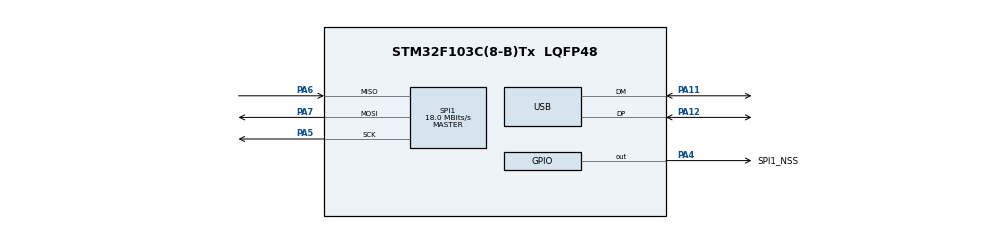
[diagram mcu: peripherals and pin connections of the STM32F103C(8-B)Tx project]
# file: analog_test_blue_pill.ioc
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Mcu.Family=STM32F1
Mcu.Name=STM32F103C(8-B)Tx
Mcu.Package=LQFP48
NVIC.PriorityGroup=NVIC_PRIORITYGROUP_4
NVIC.TIM3_IRQn=true\:0\:0\:false\:false\:true\:true
NVIC.USB_LP_CAN1_RX0_IRQn=true\:0\:0\:false\:false\:true\:true
PA11.Mode=Device
PA11.Signal=USB_DM
PA12.Mode=Device
PA12.Signal=USB_DP
PA13.Mode=Serial_Wire
PA13.Signal=SYS_JTMS-SWDIO
PA14.Mode=Serial_Wire
PA14.Signal=SYS_JTCK-SWCLK
PA4.GPIO_Label=SPI1_NSS
PA4.GPIO_Speed=GPIO_SPEED_FREQ_HIGH
PA4.Signal=GPIO_Output
PA5.Mode=Full_Duplex_Master
PA5.Signal=SPI1_SCK
PA6.Mode=Full_Duplex_Master
PA6.Signal=SPI1_MISO
PA7.Mode=Full_Duplex_Master
PA7.Signal=SPI1_MOSI
PC14-OSC32_IN.Mode=LSE-External-Oscillator
PC14-OSC32_IN.Signal=RCC_OSC32_IN
PC15-OSC32_OUT.Mode=LSE-External-Oscillator
PC15-OSC32_OUT.Signal=RCC_OSC32_OUT
PD0-OSC_IN.Mode=HSE-External-Oscillator
PD0-OSC_IN.Signal=RCC_OSC_IN
PD1-OSC_OUT.Mode=HSE-External-Oscillator
PD1-OSC_OUT.Signal=RCC_OSC_OUT
ProjectManager.HeapSize=0x200
ProjectManager.StackSize=0x400
ProjectManager.TargetToolchain=SW4STM32
RCC.ADCPresc=RCC_ADCPCLK2_DIV4
RCC.AHBFreq_Value=72000000
RCC.APB1CLKDivider=RCC_HCLK_DIV2
RCC.APB1Freq_Value=36000000
RCC.APB1TimFreq_Value=72000000
RCC.APB2Freq_Value=72000000
RCC.APB2TimFreq_Value=72000000
RCC.HCLKFreq_Value=72000000
RCC.PLLMUL=RCC_PLL_MUL9
RCC.SYSCLKFreq_VALUE=72000000
RCC.SYSCLKSource=RCC_SYSCLKSOURCE_PLLCLK
RCC.USBFreq_Value=48000000
RCC.USBPrescaler=RCC_USBCLKSOURCE_PLL_DIV1_5
RCC.VDD_VALUE=3.3
SPI1.BaudRatePrescaler=SPI_BAUDRATEPRESCALER_4
SPI1.CalculateBaudRate=18.0 MBits/s
SPI1.DataSize=SPI_DATASIZE_16BIT
SPI1.Direction=SPI_DIRECTION_2LINES
SPI1.Mode=SPI_MODE_MASTER
SPI1.VirtualType=VM_MASTER
TIM3.Period=9
TIM3.Prescaler=719
USB.ep0_mps=DEP0CTL_MPS_64
USB_DEVICE.CLASS_NAME_FS=CDC
USB_DEVICE.MANUFACTURER_STRING=Yandex, LLC.
USB_DEVICE.PRODUCT_STRING_CDC_FS=VoltaBox
USB_DEVICE.USBD_CDC_INTERVAL=10
USB_DEVICE.USBD_HandleTypeDef=hUsbDeviceFS
USB_DEVICE.USBD_SELF_POWERED=0
USB_DEVICE.USBD_SUPPORT_USER_STRING=0
USB_DEVICE.VirtualMode=Cdc
USB_DEVICE.VirtualModeFS=Cdc_FS
VP_TIM3_VS_ClockSourceINT.Mode=Internal
VP_USB_DEVICE_VS_USB_DEVICE_CDC_FS.Mode=CDC_FS
board=custom

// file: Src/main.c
/**
  ******************************************************************************
  * @file           : main.c
  * @brief          : Main program body
  ******************************************************************************
  * This notice applies to any and all portions of this file
  * that are not between comment pairs USER CODE BEGIN and
  * USER CODE END. Other portions of this file, whether
  * inserted by the user or by software development tools
  * are owned by their respective copyright owners.
  *
  * Copyright (c) 2018 STMicroelectronics International N.V.
  * All rights reserved.
  *
  * Redistribution and use in source and binary forms, with or without
  * modification, are permitted, provided that the following conditions are met:
  *
  * 1. Redistribution of source code must retain the above copyright notice,
  *    this list of conditions and the following disclaimer.
  * 2. Redistributions in binary form must reproduce the above copyright notice,
  *    this list of conditions and the following disclaimer in the documentation
  *    and/or other materials provided with the distribution.
  * 3. Neither the name of STMicroelectronics nor the names of other
  *    contributors to this software may be used to endorse or promote products
  *    derived from this software without specific written permission.
  * 4. This software, including modifications and/or derivative works of this
  *    software, must execute solely and exclusively on microcontroller or
  *    microprocessor devices manufactured by or for STMicroelectronics.
  * 5. Redistribution and use of this software other than as permitted under
  *    this license is void and will automatically terminate your rights under
  *    this license.
  *
  * THIS SOFTWARE IS PROVIDED BY STMICROELECTRONICS AND CONTRIBUTORS "AS IS"
  * AND ANY EXPRESS, IMPLIED OR STATUTORY WARRANTIES, INCLUDING, BUT NOT
  * LIMITED TO, THE IMPLIED WARRANTIES OF MERCHANTABILITY, FITNESS FOR A
  * PARTICULAR PURPOSE AND NON-INFRINGEMENT OF THIRD PARTY INTELLECTUAL PROPERTY
  * RIGHTS ARE DISCLAIMED TO THE FULLEST EXTENT PERMITTED BY LAW. IN NO EVENT
  * SHALL STMICROELECTRONICS OR CONTRIBUTORS BE LIABLE FOR ANY DIRECT, INDIRECT,
  * INCIDENTAL, SPECIAL, EXEMPLARY, OR CONSEQUENTIAL DAMAGES (INCLUDING, BUT NOT
  * LIMITED TO, PROCUREMENT OF SUBSTITUTE GOODS OR SERVICES; LOSS OF USE, DATA,
  * OR PROFITS; OR BUSINESS INTERRUPTION) HOWEVER CAUSED AND ON ANY THEORY OF
  * LIABILITY, WHETHER IN CONTRACT, STRICT LIABILITY, OR TORT (INCLUDING
  * NEGLIGENCE OR OTHERWISE) ARISING IN ANY WAY OUT OF THE USE OF THIS SOFTWARE,
  * EVEN IF ADVISED OF THE POSSIBILITY OF SUCH DAMAGE.
  *
  ******************************************************************************
  */
#include "main.h"
#include "stm32f1xx_hal.h"
#include "usb_device.h"

/* USER CODE BEGIN Includes */
#include "usbd_cdc_if.h"
#include "buffer.h"

#define SENDBUF_SIZE RINGBUF_SIZE/2
/* USER CODE END Includes */

SPI_HandleTypeDef hspi1;

TIM_HandleTypeDef htim3;

/* USER CODE BEGIN PV */
/* Private variables ---------------------------------------------------------*/
const uint8_t cmd_read_current[] = { 0x03, 0x82, 0x00, 0x00 };
const uint8_t cmd_read_voltage[] = { 0x01, 0x82, 0x00, 0x00 };
struct ringbuf_t rb;

/* USER CODE END PV */

void SystemClock_Config(void);
static void MX_GPIO_Init(void);
static void MX_SPI1_Init(void);
static void MX_TIM3_Init(void);

/* USER CODE BEGIN PFP */
/* Private function prototypes -----------------------------------------------*/

/* USER CODE END PFP */

/* USER CODE BEGIN 0 */
uint8_t overSampleCount = 0;
uint16_t overSampleISum = 0;
uint16_t overSampleUSum = 0;
void HAL_TIM_PeriodElapsedCallback(TIM_HandleTypeDef *htim) {
  if (htim->Instance == TIM3) {
    HAL_StatusTypeDef status;
    uint8_t receive_buffer[] = { 0x00, 0x00, 0x00, 0x00 };

    HAL_GPIO_WritePin(SPI1_NSS_GPIO_Port, SPI1_NSS_Pin, GPIO_PIN_RESET);
    status = HAL_SPI_TransmitReceive(&hspi1, cmd_read_current, receive_buffer,
        2, HAL_MAX_DELAY);
    HAL_GPIO_WritePin(SPI1_NSS_GPIO_Port, SPI1_NSS_Pin, GPIO_PIN_SET);
    uint16_t current_value = ((uint16_t) receive_buffer[3] << 8)
        + (uint16_t) receive_buffer[2];
    HAL_GPIO_WritePin(SPI1_NSS_GPIO_Port, SPI1_NSS_Pin, GPIO_PIN_RESET);
    status = HAL_SPI_TransmitReceive(&hspi1, cmd_read_voltage, receive_buffer,
        2, HAL_MAX_DELAY);
    HAL_GPIO_WritePin(SPI1_NSS_GPIO_Port, SPI1_NSS_Pin, GPIO_PIN_SET);
    uint16_t voltage_value = ((uint16_t) receive_buffer[3] << 8)
        + (uint16_t) receive_buffer[2];

    //rb_push(&rb, current_value);
    if(status == HAL_OK)
    {
      if(overSampleCount < 4)
      {
        overSampleISum += current_value;
        overSampleUSum += voltage_value;
        overSampleCount++;
      }
      else
      {
        overSampleCount = 0;
        rb_push(&rb, overSampleISum);
        //rb_push(&rb, overSampleUSum);
        overSampleISum = 0;
        overSampleUSum = 0;
      }
    }
  }
}
/* USER CODE END 0 */

int main(void)
{
  /* USER CODE BEGIN 1 */
  uint16_t buff[16];
  rb_init(&rb);

  /* USER CODE END 1 */

  /* MCU Configuration----------------------------------------------------------*/

  /* Reset of all peripherals, Initializes the Flash interface and the Systick. */
  HAL_Init();

  /* Configure the system clock */
  SystemClock_Config();

  /* Initialize all configured peripherals */
  MX_GPIO_Init();
  MX_USB_DEVICE_Init();
  MX_SPI1_Init();
  MX_TIM3_Init();
  /* USER CODE BEGIN 2 */

  // wait USB enumeration
  HAL_Delay(1000);

  HAL_TIM_Base_Start_IT(&htim3);

  /* USER CODE END 2 */

  /* Infinite loop */
  while (1) {

  /* USER CODE BEGIN 3 */
    if (rb_remain(&rb) > SENDBUF_SIZE) {
      for (int i = 0; i < SENDBUF_SIZE; i++)
        buff[i] = rb_pop(&rb);
      while (CDC_Transmit_FS((uint8_t*) buff, sizeof(buff)) == USBD_BUSY)
        ;
    }

  }
  /* USER CODE END 3 */

}

void SystemClock_Config(void)
{

  RCC_OscInitTypeDef RCC_OscInitStruct;
  RCC_ClkInitTypeDef RCC_ClkInitStruct;
  RCC_PeriphCLKInitTypeDef PeriphClkInit;

    /**Initializes the CPU, AHB and APB busses clocks
    */
  RCC_OscInitStruct.OscillatorType = RCC_OSCILLATORTYPE_HSE;
  RCC_OscInitStruct.HSEState = RCC_HSE_ON;
  RCC_OscInitStruct.HSEPredivValue = RCC_HSE_PREDIV_DIV1;
  RCC_OscInitStruct.HSIState = RCC_HSI_ON;
  RCC_OscInitStruct.PLL.PLLState = RCC_PLL_ON;
  RCC_OscInitStruct.PLL.PLLSource = RCC_PLLSOURCE_HSE;
  RCC_OscInitStruct.PLL.PLLMUL = RCC_PLL_MUL6;
  if (HAL_RCC_OscConfig(&RCC_OscInitStruct) != HAL_OK)
  {
    _Error_Handler(__FILE__, __LINE__);
  }

    /**Initializes the CPU, AHB and APB busses clocks
    */
  RCC_ClkInitStruct.ClockType = RCC_CLOCKTYPE_HCLK|RCC_CLOCKTYPE_SYSCLK
                              |RCC_CLOCKTYPE_PCLK1|RCC_CLOCKTYPE_PCLK2;
  RCC_ClkInitStruct.SYSCLKSource = RCC_SYSCLKSOURCE_PLLCLK;
  RCC_ClkInitStruct.AHBCLKDivider = RCC_SYSCLK_DIV1;
  RCC_ClkInitStruct.APB1CLKDivider = RCC_HCLK_DIV2;
  RCC_ClkInitStruct.APB2CLKDivider = RCC_HCLK_DIV1;

  if (HAL_RCC_ClockConfig(&RCC_ClkInitStruct, FLASH_LATENCY_1) != HAL_OK)
  {
    _Error_Handler(__FILE__, __LINE__);
  }

  PeriphClkInit.PeriphClockSelection = RCC_PERIPHCLK_USB;
  PeriphClkInit.UsbClockSelection = RCC_USBCLKSOURCE_PLL;
  if (HAL_RCCEx_PeriphCLKConfig(&PeriphClkInit) != HAL_OK)
  {
    _Error_Handler(__FILE__, __LINE__);
  }

    /**Configure the Systick interrupt time
    */
  HAL_SYSTICK_Config(HAL_RCC_GetHCLKFreq()/1000);

    /**Configure the Systick
    */
  HAL_SYSTICK_CLKSourceConfig(SYSTICK_CLKSOURCE_HCLK);

  /* SysTick_IRQn interrupt configuration */
  HAL_NVIC_SetPriority(SysTick_IRQn, 0, 0);
}

/* SPI1 init function */
static void MX_SPI1_Init(void)
{

  /* SPI1 parameter configuration*/
  hspi1.Instance = SPI1;
  hspi1.Init.Mode = SPI_MODE_MASTER;
  hspi1.Init.Direction = SPI_DIRECTION_2LINES;
  hspi1.Init.DataSize = SPI_DATASIZE_16BIT;
  hspi1.Init.CLKPolarity = SPI_POLARITY_LOW;
  hspi1.Init.CLKPhase = SPI_PHASE_1EDGE;
  hspi1.Init.NSS = SPI_NSS_SOFT;
  hspi1.Init.BaudRatePrescaler = SPI_BAUDRATEPRESCALER_4;
  hspi1.Init.FirstBit = SPI_FIRSTBIT_MSB;
  hspi1.Init.TIMode = SPI_TIMODE_DISABLE;
  hspi1.Init.CRCCalculation = SPI_CRCCALCULATION_DISABLE;
  hspi1.Init.CRCPolynomial = 10;
  if (HAL_SPI_Init(&hspi1) != HAL_OK)
  {
    _Error_Handler(__FILE__, __LINE__);
  }

}

/* TIM3 init function */
static void MX_TIM3_Init(void)
{

  TIM_ClockConfigTypeDef sClockSourceConfig;
  TIM_MasterConfigTypeDef sMasterConfig;

  htim3.Instance = TIM3;
  htim3.Init.Prescaler = 119;
  htim3.Init.CounterMode = TIM_COUNTERMODE_UP;
  htim3.Init.Period = 9;
  htim3.Init.ClockDivision = TIM_CLOCKDIVISION_DIV1;
  htim3.Init.AutoReloadPreload = TIM_AUTORELOAD_PRELOAD_DISABLE;
  if (HAL_TIM_Base_Init(&htim3) != HAL_OK)
  {
    _Error_Handler(__FILE__, __LINE__);
  }

  sClockSourceConfig.ClockSource = TIM_CLOCKSOURCE_INTERNAL;
  if (HAL_TIM_ConfigClockSource(&htim3, &sClockSourceConfig) != HAL_OK)
  {
    _Error_Handler(__FILE__, __LINE__);
  }

  sMasterConfig.MasterOutputTrigger = TIM_TRGO_RESET;
  sMasterConfig.MasterSlaveMode = TIM_MASTERSLAVEMODE_DISABLE;
  if (HAL_TIMEx_MasterConfigSynchronization(&htim3, &sMasterConfig) != HAL_OK)
  {
    _Error_Handler(__FILE__, __LINE__);
  }

}

/** Configure pins as
        * Analog
        * Input
        * Output
        * EVENT_OUT
        * EXTI
*/
static void MX_GPIO_Init(void)
{

  GPIO_InitTypeDef GPIO_InitStruct;

  /* GPIO Ports Clock Enable */
  __HAL_RCC_GPIOC_CLK_ENABLE();
  __HAL_RCC_GPIOD_CLK_ENABLE();
  __HAL_RCC_GPIOA_CLK_ENABLE();

  /*Configure GPIO pin Output Level */
  HAL_GPIO_WritePin(SPI1_NSS_GPIO_Port, SPI1_NSS_Pin, GPIO_PIN_RESET);

  /*Configure GPIO pin : SPI1_NSS_Pin */
  GPIO_InitStruct.Pin = SPI1_NSS_Pin;
  GPIO_InitStruct.Mode = GPIO_MODE_OUTPUT_PP;
  GPIO_InitStruct.Pull = GPIO_NOPULL;
  GPIO_InitStruct.Speed = GPIO_SPEED_FREQ_HIGH;
  HAL_GPIO_Init(SPI1_NSS_GPIO_Port, &GPIO_InitStruct);

}

void _Error_Handler(char *file, int line)
{
  while (1) {
  }
}

/************************ (C) COPYRIGHT STMicroelectronics *****END OF FILE****/
